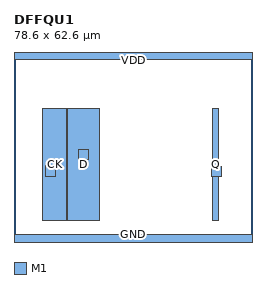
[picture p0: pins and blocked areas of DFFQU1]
MACRO DFFQU1
  CLASS CORE ;
  ORIGIN 0 0 ;
  SIZE 78.600 BY 62.600 ;
  SYMMETRY X Y ;
  SITE TR1um_site ;
  PIN D
    DIRECTION INPUT ; USE SIGNAL ;
    PORT
      LAYER M1 ;
        RECT 17.500 7.200 28.100 44.000 ;
      LAYER M1 ;
        RECT 21.100 27.100 24.500 30.500 ;
    END
  END D
  PIN CK
    DIRECTION INPUT ; USE SIGNAL ;
    PORT
      LAYER M1 ;
        RECT 9.500 7.200 17.300 44.000 ;
      LAYER M1 ;
        RECT 10.300 21.700 13.700 25.100 ;
    END
  END CK
  PIN Q
    DIRECTION OUTPUT ; USE SIGNAL ;
    PORT
      LAYER M1 ;
        RECT 65.500 7.200 67.300 44.000 ;
      LAYER M1 ;
        RECT 65.100 21.600 68.500 25.000 ;
    END
  END Q
  PIN GND
    DIRECTION INOUT ; USE GROUND ;
    PORT
      LAYER M1 ;
        RECT 0.000 0.000 78.600 2.600 ;
    END
  END GND
  PIN VDD
    DIRECTION INOUT ; USE POWER ;
    PORT
      LAYER M1 ;
        RECT 0.000 60.000 78.600 62.600 ;
    END
  END VDD
END DFFQU1
